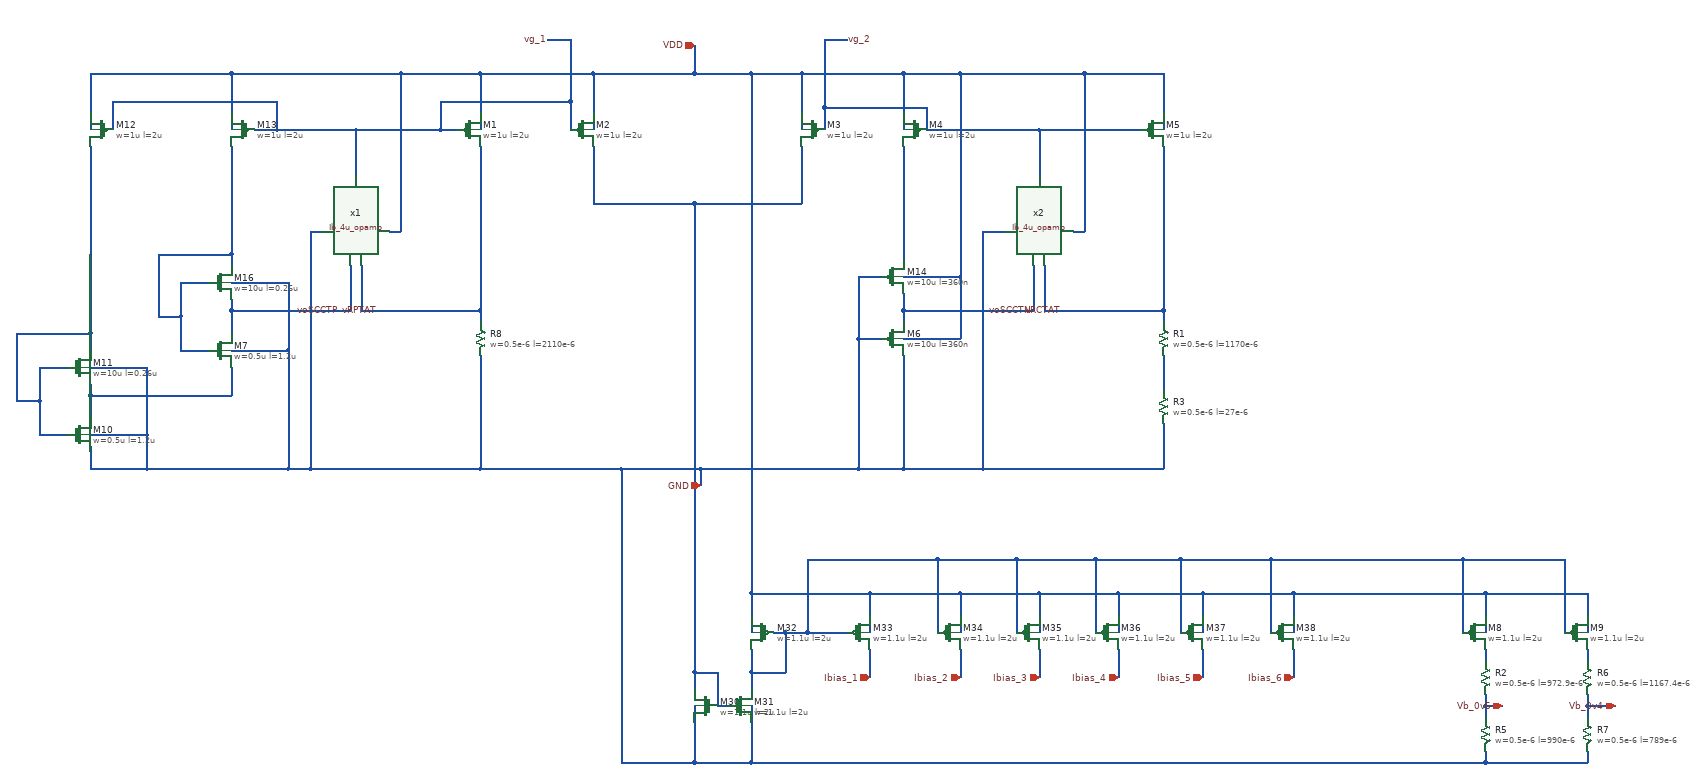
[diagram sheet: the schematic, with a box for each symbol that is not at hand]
v {xschem version=3.4.6 file_version=1.2}
G {}
K {}
V {}
S {}
E {}
N 1800 -1200 1800 -1160 {lab=vg_2}
N 1680 -900 1720 -900 {lab=GND}
N 1680 -790 1720 -790 {lab=GND}
N 1760 -840 1760 -820 {lab=voSCCTN}
N 2000 -1160 2000 -1080 {lab=vg_2}
N 1800 -1160 2000 -1160 {lab=vg_2}
N 1210 -1260 1210 -1160 {lab=VDD}
N 1580 -1260 1580 -1160 {lab=VDD}
N 1760 -1260 1760 -1160 {lab=VDD}
N 2220 -1260 2220 -1160 {lab=VDD}
N 320 -1260 570 -1260 {lab=VDD}
N 1010 -1260 1010 -1160 {lab=VDD}
N 870 -1260 1010 -1260 {lab=VDD}
N 940 -1160 970 -1160 {lab=vg_1}
N 940 -1210 940 -1160 {lab=vg_1}
N 1170 -1210 1170 -1160 {lab=vg_1}
N 1620 -1200 1620 -1160 {lab=vg_2}
N 790 -1160 940 -1160 {lab=vg_1}
N 570 -1260 570 -1160 {lab=VDD}
N 790 -1160 790 -1080 {lab=vg_1}
N 650 -1160 790 -1160 {lab=vg_1}
N 850 -980 870 -980 {lab=VDD}
N 870 -1260 870 -980 {lab=VDD}
N 570 -1260 870 -1260 {lab=VDD}
N 570 -840 570 -800 {lab=voSCCTP}
N 570 -890 670 -890 {lab=GND}
N 670 -890 670 -770 {lab=GND}
N 570 -770 670 -770 {lab=GND}
N 480 -890 530 -890 {lab=#net1}
N 480 -830 480 -770 {lab=#net1}
N 480 -770 530 -770 {lab=#net1}
N 570 -940 570 -920 {lab=#net1}
N 440 -830 480 -830 {lab=#net1}
N 480 -890 480 -830 {lab=#net1}
N 440 -940 440 -830 {lab=#net1}
N 440 -940 570 -940 {lab=#net1}
N 570 -1130 570 -940 {lab=#net1}
N 570 -840 780 -840 {lab=voSCCTP}
N 570 -860 570 -840 {lab=voSCCTP}
N 780 -920 780 -840 {lab=voSCCTP}
N 320 -690 320 -650 {lab=#net2}
N 320 -740 420 -740 {lab=GND}
N 420 -740 420 -620 {lab=GND}
N 320 -620 420 -620 {lab=GND}
N 230 -740 280 -740 {lab=#net3}
N 230 -680 230 -620 {lab=#net3}
N 230 -620 280 -620 {lab=#net3}
N 190 -680 230 -680 {lab=#net3}
N 230 -740 230 -680 {lab=#net3}
N 320 -690 570 -690 {lab=#net2}
N 320 -710 320 -690 {lab=#net2}
N 570 -740 570 -690 {lab=#net2}
N 320 -800 320 -770 {lab=#net3}
N 320 -1260 320 -1160 {lab=VDD}
N 360 -1210 360 -1160 {lab=vg_1}
N 360 -1210 650 -1210 {lab=vg_1}
N 650 -1210 650 -1160 {lab=vg_1}
N 610 -1160 650 -1160 {lab=vg_1}
N 320 -600 320 -560 {lab=GND}
N 190 -800 190 -680 {lab=#net3}
N 190 -800 320 -800 {lab=#net3}
N 320 -1130 320 -800 {lab=#net3}
N 1680 -900 1680 -790 {lab=GND}
N 1900 -560 2220 -560 {lab=GND}
N 670 -770 670 -560 {lab=GND}
N 420 -560 670 -560 {lab=GND}
N 420 -620 420 -560 {lab=GND}
N 320 -560 420 -560 {lab=GND}
N 1760 -790 1860 -790 {lab=VDD}
N 2080 -1260 2220 -1260 {lab=VDD}
N 1010 -840 1010 -820 {lab=vRPTAT}
N 1010 -760 1010 -560 {lab=GND}
N 710 -560 1010 -560 {lab=GND}
N 800 -920 800 -840 {lab=vRPTAT}
N 800 -840 1010 -840 {lab=vRPTAT}
N 1010 -1130 1010 -840 {lab=vRPTAT}
N 2220 -840 2220 -820 {lab=vRCTAT}
N 2010 -840 2220 -840 {lab=vRCTAT}
N 2220 -1130 2220 -840 {lab=vRCTAT}
N 2010 -920 2010 -840 {lab=vRCTAT}
N 1990 -920 1990 -840 {lab=voSCCTN}
N 1760 -1130 1760 -930 {lab=#net4}
N 1760 -760 1760 -560 {lab=GND}
N 1760 -840 1990 -840 {lab=voSCCTN}
N 1760 -870 1760 -840 {lab=voSCCTN}
N 1860 -900 1860 -790 {lab=VDD}
N 1760 -1260 1860 -1260 {lab=VDD}
N 1900 -980 1940 -980 {lab=GND}
N 1900 -980 1900 -560 {lab=GND}
N 1760 -560 1900 -560 {lab=GND}
N 2060 -980 2080 -980 {lab=VDD}
N 2080 -1260 2080 -980 {lab=VDD}
N 1860 -1260 2080 -1260 {lab=VDD}
N 1680 -560 1760 -560 {lab=GND}
N 1680 -790 1680 -560 {lab=GND}
N 1620 -1200 1800 -1200 {lab=vg_2}
N 940 -1210 1170 -1210 {lab=vg_1}
N 1010 -1260 1210 -1260 {lab=VDD}
N 1580 -1260 1760 -1260 {lab=VDD}
N 1490 -1260 1580 -1260 {lab=VDD}
N 710 -980 730 -980 {lab=GND}
N 710 -980 710 -560 {lab=GND}
N 670 -560 710 -560 {lab=GND}
N 1760 -900 1860 -900 {lab=VDD}
N 1860 -1260 1860 -900 {lab=VDD}
N 1390 -1030 1580 -1030 {lab=#net5}
N 1210 -1130 1210 -1030 {lab=#net5}
N 1580 -1130 1580 -1030 {lab=#net5}
N 1210 -1030 1390 -1030 {lab=#net5}
N 1390 -1310 1390 -1260 {lab=VDD}
N 1210 -1260 1390 -1260 {lab=VDD}
N 1400 -560 1680 -560 {lab=GND}
N 1400 -560 1400 -530 {lab=GND}
N 1260 -560 1400 -560 {lab=GND}
N 1170 -1320 1170 -1210 {lab=vg_1}
N 1130 -1320 1170 -1320 {lab=vg_1}
N 1620 -1320 1660 -1320 {lab=vg_2}
N 1620 -1320 1620 -1200 {lab=vg_2}
N 2000 -1160 2180 -1160 {lab=vg_2}
N 1260 -560 1260 -40 {lab=GND}
N 1010 -560 1260 -560 {lab=GND}
N 1390 -140 1390 -40 {lab=GND}
N 1390 -200 1390 -170 {lab=#net5}
N 1430 -140 1450 -140 {lab=#net5}
N 1260 -40 1390 -40 {lab=GND}
N 1390 -1260 1490 -1260 {lab=VDD}
N 1430 -200 1430 -140 {lab=#net5}
N 1390 -200 1430 -200 {lab=#net5}
N 1390 -1030 1390 -200 {lab=#net5}
N 1490 -200 1490 -170 {lab=#net6}
N 1390 -40 1490 -40 {lab=GND}
N 1700 -340 1860 -340 {lab=VDD}
N 1490 -340 1490 -270 {lab=VDD}
N 1590 -270 1660 -270 {lab=#net6}
N 1860 -340 1860 -270 {lab=VDD}
N 2000 -340 2000 -270 {lab=VDD}
N 1860 -340 2000 -340 {lab=VDD}
N 1700 -240 1700 -190 {lab=Ibias_1}
N 2140 -340 2140 -270 {lab=VDD}
N 2000 -340 2140 -340 {lab=VDD}
N 2290 -340 2290 -270 {lab=VDD}
N 2140 -340 2290 -340 {lab=VDD}
N 2450 -340 2450 -270 {lab=VDD}
N 2290 -340 2450 -340 {lab=VDD}
N 2790 -340 2790 -270 {lab=VDD}
N 1490 -140 1490 -40 {lab=GND}
N 1590 -400 1590 -270 {lab=#net6}
N 1550 -270 1590 -270 {lab=#net6}
N 2450 -240 2450 -190 {lab=Ibias_6}
N 2290 -240 2290 -190 {lab=Ibias_5}
N 2140 -240 2140 -190 {lab=Ibias_4}
N 2000 -240 2000 -190 {lab=Ibias_3}
N 1860 -240 1860 -190 {lab=Ibias_2}
N 1700 -340 1700 -270 {lab=VDD}
N 1490 -340 1700 -340 {lab=VDD}
N 1490 -1260 1490 -340 {lab=VDD}
N 2750 -400 2750 -270 {lab=#net6}
N 2410 -400 2410 -270 {lab=#net6}
N 2250 -400 2410 -400 {lab=#net6}
N 2250 -400 2250 -270 {lab=#net6}
N 2100 -400 2250 -400 {lab=#net6}
N 2100 -400 2100 -270 {lab=#net6}
N 1960 -400 2100 -400 {lab=#net6}
N 1960 -400 1960 -270 {lab=#net6}
N 1820 -400 1960 -400 {lab=#net6}
N 1820 -400 1820 -270 {lab=#net6}
N 1590 -400 1820 -400 {lab=#net6}
N 1490 -200 1550 -200 {lab=#net6}
N 1490 -240 1490 -200 {lab=#net6}
N 1550 -270 1550 -200 {lab=#net6}
N 1530 -270 1550 -270 {lab=#net6}
N 2790 -240 2790 -220 {lab=#net7}
N 2790 -60 2790 -40 {lab=GND}
N 2790 -140 2790 -120 {lab=Vb_0v5}
N 2790 -140 2820 -140 {lab=Vb_0v5}
N 2790 -160 2790 -140 {lab=Vb_0v5}
N 2790 -340 2970 -340 {lab=VDD}
N 2970 -340 2970 -270 {lab=VDD}
N 2750 -400 2930 -400 {lab=#net6}
N 2930 -400 2930 -270 {lab=#net6}
N 2970 -240 2970 -220 {lab=#net8}
N 2970 -140 2970 -120 {lab=Vb_0v4}
N 2790 -40 2970 -40 {lab=GND}
N 2970 -60 2970 -40 {lab=GND}
N 2970 -140 3020 -140 {lab=Vb_0v4}
N 2970 -160 2970 -140 {lab=Vb_0v4}
N 2220 -760 2220 -700 {lab=#net9}
N 2220 -640 2220 -560 {lab=GND}
N 2410 -400 2750 -400 {lab=#net6}
N 2450 -340 2790 -340 {lab=VDD}
N 1490 -40 2790 -40 {lab=GND}
C {iopin.sym} 1390 -1310 0 0 {name=p1 lab=VDD}
C {iopin.sym} 1400 -530 0 0 {name=p2 lab=GND}
C {iopin.sym} 1700 -190 0 0 {name=p3 lab=Ibias_1}
C {lab_pin.sym} 760 -840 3 0 {name=p9 sig_type=std_logic lab=voSCCTP}
C {lab_pin.sym} 1990 -840 3 0 {name=p10 sig_type=std_logic lab=voSCCTN}
C {lab_pin.sym} 2040 -840 3 0 {name=p11 sig_type=std_logic lab=vRCTAT}
C {lab_pin.sym} 830 -840 3 0 {name=p12 sig_type=std_logic lab=vRPTAT}
C {sg13g2_pr/sg13_lv_pmos.sym} 990 -1160 0 0 {name=M1
l=2u
w=1u
ng=1
m=1
model=sg13_lv_pmos
spiceprefix=X
}
C {sg13g2_pr/sg13_lv_pmos.sym} 1190 -1160 0 0 {name=M2
l=2u
w=1u
ng=1
m=6
model=sg13_lv_pmos
spiceprefix=X
}
C {sg13g2_pr/sg13_lv_pmos.sym} 1600 -1160 0 1 {name=M3
l=2u
w=1u
ng=1
m=6
model=sg13_lv_pmos
spiceprefix=X
}
C {sg13g2_pr/sg13_lv_pmos.sym} 1780 -1160 0 1 {name=M4
l=2u
w=1u
ng=1
m=1
model=sg13_lv_pmos
spiceprefix=X
}
C {sg13g2_pr/sg13_lv_pmos.sym} 340 -1160 0 1 {name=M12
l=2u
w=1u
ng=1
m=1
model=sg13_lv_pmos
spiceprefix=X
}
C {sg13g2_pr/sg13_lv_pmos.sym} 590 -1160 0 1 {name=M13
l=2u
w=1u
ng=1
m=1
model=sg13_lv_pmos
spiceprefix=X
}
C {sg13g2_pr/sg13_lv_pmos.sym} 2200 -1160 0 0 {name=M5
l=2u
w=1u
ng=1
m=1
model=sg13_lv_pmos
spiceprefix=X
}
C {sg13g2_pr/sg13_lv_nmos.sym} 550 -770 0 0 {name=M7
l=1.2u
w=0.5u
ng=1
m=1
model=sg13_lv_nmos
spiceprefix=X
}
C {sg13g2_pr/sg13_lv_nmos.sym} 300 -620 0 0 {name=M10
l=1.2u
w=0.5u
ng=1
m=1
model=sg13_lv_nmos
spiceprefix=X
}
C {sg13g2_pr/sg13_lv_nmos.sym} 300 -740 0 0 {name=M11
l=0.26u
w=10u
ng=1
m=30
model=sg13_lv_nmos
spiceprefix=X
}
C {sg13g2_pr/sg13_lv_nmos.sym} 550 -890 0 0 {name=M16
l=0.26u
w=10u
ng=1
m=30
model=sg13_lv_nmos
spiceprefix=X
}
C {sg13g2_pr/sg13_lv_pmos.sym} 1740 -790 0 0 {name=M6
l=360n
w=10u
ng=1
m=20
model=sg13_lv_pmos
spiceprefix=X
}
C {sg13g2_pr/sg13_lv_pmos.sym} 1740 -900 0 0 {name=M14
l=360n
w=10u
ng=1
m=1
model=sg13_lv_pmos
spiceprefix=X
}
C {iopin.sym} 1860 -190 0 0 {name=p4 lab=Ibias_2}
C {iopin.sym} 2000 -190 0 0 {name=p5 lab=Ibias_3}
C {iopin.sym} 2140 -190 0 0 {name=p6 lab=Ibias_4}
C {iopin.sym} 2290 -190 0 0 {name=p7 lab=Ibias_5}
C {iopin.sym} 2450 -190 0 0 {name=p8 lab=Ibias_6}
C {lab_pin.sym} 1130 -1320 0 0 {name=p14 sig_type=std_logic lab=vg_1}
C {lab_pin.sym} 1660 -1320 0 1 {name=p15 sig_type=std_logic lab=vg_2}
C {/shared/designs/SSDOR_w_startup_1V_ihp/Ib_4u/Ib_4u_opamp/Ib_4u_opamp.sym} 730 -920 1 1 {name=x1}
C {/shared/designs/SSDOR_w_startup_1V_ihp/Ib_4u/Ib_4u_opamp/Ib_4u_opamp.sym} 1940 -920 1 1 {name=x2}
C {sg13g2_pr/sg13_lv_nmos.sym} 1410 -140 0 1 {name=M30
l=2u
w=1.1u
ng=1
m=3
model=sg13_lv_nmos
spiceprefix=X
}
C {sg13g2_pr/sg13_lv_nmos.sym} 1470 -140 0 0 {name=M31
l=2u
w=1.1u
ng=1
m=3
model=sg13_lv_nmos
spiceprefix=X
}
C {sg13g2_pr/sg13_lv_pmos.sym} 1510 -270 0 1 {name=M32
l=2u
w=1.1u
ng=1
m=6
model=sg13_lv_pmos
spiceprefix=X
}
C {sg13g2_pr/sg13_lv_pmos.sym} 1680 -270 0 0 {name=M33
l=2u
w=1.1u
ng=1
m=6
model=sg13_lv_pmos
spiceprefix=X
}
C {sg13g2_pr/sg13_lv_pmos.sym} 1840 -270 0 0 {name=M34
l=2u
w=1.1u
ng=1
m=6
model=sg13_lv_pmos
spiceprefix=X
}
C {sg13g2_pr/sg13_lv_pmos.sym} 1980 -270 0 0 {name=M35
l=2u
w=1.1u
ng=1
m=6
model=sg13_lv_pmos
spiceprefix=X
}
C {sg13g2_pr/sg13_lv_pmos.sym} 2120 -270 0 0 {name=M36
l=2u
w=1.1u
ng=1
m=6
model=sg13_lv_pmos
spiceprefix=X
}
C {sg13g2_pr/sg13_lv_pmos.sym} 2270 -270 0 0 {name=M37
l=2u
w=1.1u
ng=1
m=6
model=sg13_lv_pmos
spiceprefix=X
}
C {sg13g2_pr/sg13_lv_pmos.sym} 2430 -270 0 0 {name=M38
l=2u
w=1.1u
ng=1
m=6
model=sg13_lv_pmos
spiceprefix=X
}
C {sg13g2_pr/sg13_lv_pmos.sym} 2770 -270 0 0 {name=M8
l=2u
w=1.1u
ng=1
m=6
model=sg13_lv_pmos
spiceprefix=X
}
C {sg13g2_pr/rppd.sym} 2790 -190 0 0 {name=R2
w=0.5e-6
l=972.9e-6
model=rppd
body=GND
spiceprefix=X
b=0
m=1
}
C {sg13g2_pr/sg13_lv_pmos.sym} 2950 -270 0 0 {name=M9
l=2u
w=1.1u
ng=1
m=6
model=sg13_lv_pmos
spiceprefix=X
}
C {sg13g2_pr/rppd.sym} 2970 -190 0 0 {name=R6
w=0.5e-6
l=1167.4e-6
model=rppd
body=GND
spiceprefix=X
b=0
m=1
}
C {sg13g2_pr/rppd.sym} 2970 -90 0 0 {name=R7
w=0.5e-6
l=789e-6
model=rppd
body=GND
spiceprefix=X
b=0
m=1
}
C {iopin.sym} 3020 -140 0 0 {name=p16 lab=Vb_0v4}
C {iopin.sym} 2820 -140 0 0 {name=p17 lab=Vb_0v5}
C {sg13g2_pr/rppd.sym} 2790 -90 0 0 {name=R5
w=0.5e-6
l=990e-6
model=rppd
body=GND
spiceprefix=X
b=0
m=1
}
C {sg13g2_pr/rppd.sym} 1010 -790 0 0 {name=R8
w=0.5e-6
l=2110e-6
model=rppd
body=GND
spiceprefix=X
b=0
m=1
}
C {sg13g2_pr/rppd.sym} 2220 -790 0 0 {name=R1
w=0.5e-6
l=1170e-6
model=rppd
body=GND
spiceprefix=X
b=0
m=1
}
C {sg13g2_pr/rhigh.sym} 2220 -670 0 0 {name=R3
w=0.5e-6
l=27e-6
model=rhigh
body=GND
spiceprefix=X
b=0
m=1
}
